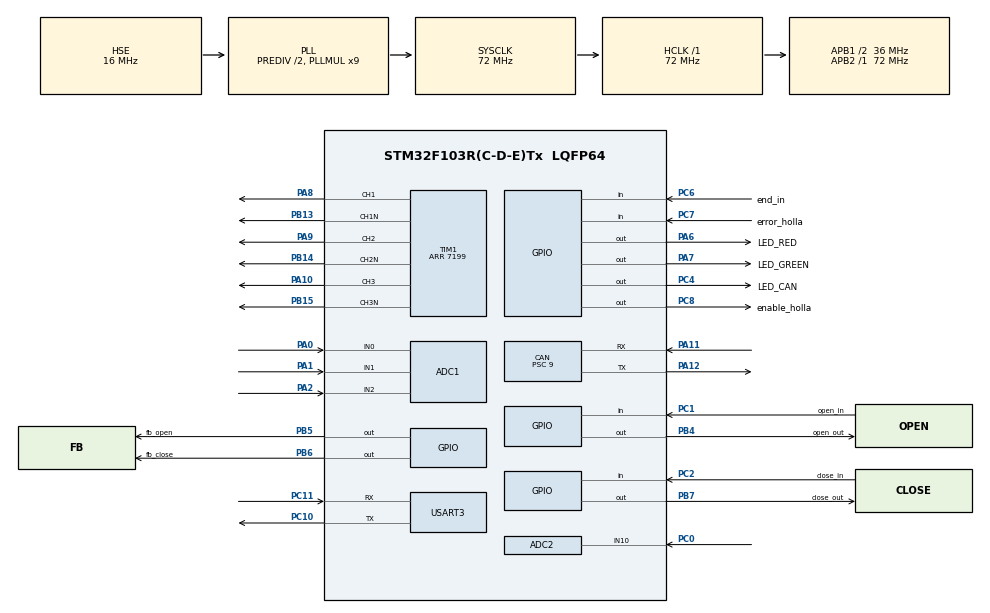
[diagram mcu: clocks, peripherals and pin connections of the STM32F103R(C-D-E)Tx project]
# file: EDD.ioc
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ADC1.Channel-0\#ChannelRegularConversion=ADC_CHANNEL_0
ADC1.Channel-1\#ChannelRegularConversion=ADC_CHANNEL_1
ADC1.Channel-2\#ChannelRegularConversion=ADC_CHANNEL_2
ADC1.NbrOfConversion=3
ADC1.NbrOfConversionFlag=1
ADC1.Rank-0\#ChannelRegularConversion=1
ADC1.Rank-1\#ChannelRegularConversion=2
ADC1.Rank-2\#ChannelRegularConversion=3
ADC1.SamplingTime-0\#ChannelRegularConversion=ADC_SAMPLETIME_13CYCLES_5
ADC1.SamplingTime-1\#ChannelRegularConversion=ADC_SAMPLETIME_13CYCLES_5
ADC1.SamplingTime-2\#ChannelRegularConversion=ADC_SAMPLETIME_13CYCLES_5
ADC1.master=1
ADC2.Channel-1\#ChannelInjectedConversion=ADC_CHANNEL_10
ADC2.EnableInjectedConversion=ENABLE
ADC2.EnableRegularConversion=DISABLE
ADC2.InjNumberOfConversion=1
ADC2.InjectedOffset-1\#ChannelInjectedConversion=0
ADC2.InjectedRank-1\#ChannelInjectedConversion=1
ADC2.SamplingTime-1\#ChannelInjectedConversion=ADC_SAMPLETIME_13CYCLES_5
CAN.ABOM=ENABLE
CAN.BS1=CAN_BS1_12TQ
CAN.BS2=CAN_BS2_3TQ
CAN.CalculateBaudRate=250000
CAN.CalculateTimeBit=4000
CAN.CalculateTimeQuantum=250.0
CAN.NART=ENABLE
CAN.Prescaler=9
CAN.TXFP=ENABLE
Dma.ADC1.0.Direction=DMA_PERIPH_TO_MEMORY
Dma.ADC1.0.Instance=DMA1_Channel1
Dma.ADC1.0.MemDataAlignment=DMA_MDATAALIGN_HALFWORD
Dma.ADC1.0.MemInc=DMA_MINC_ENABLE
Dma.ADC1.0.Mode=DMA_NORMAL
Dma.ADC1.0.PeriphDataAlignment=DMA_PDATAALIGN_HALFWORD
Dma.ADC1.0.PeriphInc=DMA_PINC_DISABLE
Dma.ADC1.0.Priority=DMA_PRIORITY_LOW
Dma.Request0=ADC1
Dma.Request1=USART3_TX
Dma.Request2=USART3_RX
Dma.USART3_RX.2.Direction=DMA_PERIPH_TO_MEMORY
Dma.USART3_RX.2.Instance=DMA1_Channel3
Dma.USART3_RX.2.MemDataAlignment=DMA_MDATAALIGN_BYTE
Dma.USART3_RX.2.MemInc=DMA_MINC_ENABLE
Dma.USART3_RX.2.Mode=DMA_NORMAL
Dma.USART3_RX.2.PeriphDataAlignment=DMA_PDATAALIGN_BYTE
Dma.USART3_RX.2.PeriphInc=DMA_PINC_DISABLE
Dma.USART3_RX.2.Priority=DMA_PRIORITY_LOW
Dma.USART3_TX.1.Direction=DMA_MEMORY_TO_PERIPH
Dma.USART3_TX.1.Instance=DMA1_Channel2
Dma.USART3_TX.1.MemDataAlignment=DMA_MDATAALIGN_BYTE
Dma.USART3_TX.1.MemInc=DMA_MINC_ENABLE
Dma.USART3_TX.1.Mode=DMA_NORMAL
Dma.USART3_TX.1.PeriphDataAlignment=DMA_PDATAALIGN_BYTE
Dma.USART3_TX.1.PeriphInc=DMA_PINC_DISABLE
Dma.USART3_TX.1.Priority=DMA_PRIORITY_LOW
Mcu.Family=STM32F1
Mcu.Name=STM32F103R(C-D-E)Tx
Mcu.Package=LQFP64
NVIC.ADC1_2_IRQn=true\:0\:0\:false\:false\:true\:true\:true
NVIC.DMA1_Channel1_IRQn=true\:0\:0\:false\:false\:true\:false\:true
NVIC.DMA1_Channel2_IRQn=true\:0\:0\:false\:false\:true\:false\:true
NVIC.DMA1_Channel3_IRQn=true\:0\:0\:false\:false\:true\:false\:true
NVIC.PriorityGroup=NVIC_PRIORITYGROUP_4
NVIC.TIM3_IRQn=true\:2\:0\:true\:false\:true\:true\:true
NVIC.USART3_IRQn=true\:0\:0\:false\:false\:true\:true\:true
NVIC.USB_LP_CAN1_RX0_IRQn=true\:0\:0\:false\:false\:true\:true\:true
PA0-WKUP.Signal=ADCx_IN0
PA1.Signal=ADCx_IN1
PA10.Signal=S_TIM1_CH3
PA11.Mode=CAN_Activate
PA11.Signal=CAN_RX
PA12.Mode=CAN_Activate
PA12.Signal=CAN_TX
PA13.Mode=Serial_Wire
PA13.Signal=SYS_JTMS-SWDIO
PA14.Mode=Serial_Wire
PA14.Signal=SYS_JTCK-SWCLK
PA2.Signal=ADCx_IN2
PA6.GPIO_Label=LED_RED
PA6.Signal=GPIO_Output
PA7.GPIO_Label=LED_GREEN
PA7.Signal=GPIO_Output
PA8.Signal=S_TIM1_CH1
PA9.Signal=S_TIM1_CH2
PB13.Mode=PWM Generation1 CH1 CH1N
PB13.Signal=TIM1_CH1N
PB14.Mode=PWM Generation2 CH2 CH2N
PB14.Signal=TIM1_CH2N
PB15.Mode=PWM Generation3 CH3 CH3N
PB15.Signal=TIM1_CH3N
PB4.GPIO_Label=open_out
PB4.Signal=GPIO_Output
PB5.GPIO_Label=fb_open
PB5.Signal=GPIO_Output
PB6.GPIO_Label=fb_close
PB6.Signal=GPIO_Output
PB7.GPIO_Label=close_out
PB7.Signal=GPIO_Output
PC0.Signal=ADCx_IN10
PC1.GPIO_Label=open_in
PC1.Signal=GPIO_Input
PC10.Mode=Asynchronous
PC10.Signal=USART3_TX
PC11.Mode=Asynchronous
PC11.Signal=USART3_RX
PC2.GPIO_Label=close_in
PC2.Signal=GPIO_Input
PC4.GPIO_Label=LED_CAN
PC4.Signal=GPIO_Output
PC6.GPIO_Label=end_in
PC6.Signal=GPIO_Input
PC7.GPIO_Label=error_holla
PC7.Signal=GPIO_Input
PC8.GPIO_Label=enable_holla
PC8.Signal=GPIO_Output
PD0-OSC_IN.Mode=HSE-External-Oscillator
PD0-OSC_IN.Signal=RCC_OSC_IN
PD1-OSC_OUT.Mode=HSE-External-Oscillator
PD1-OSC_OUT.Signal=RCC_OSC_OUT
ProjectManager.HeapSize=0x200
ProjectManager.StackSize=0x400
ProjectManager.TargetToolchain=STM32CubeIDE
RCC.ADCPresc=RCC_ADCPCLK2_DIV6
RCC.AHBFreq_Value=72000000
RCC.APB1CLKDivider=RCC_HCLK_DIV2
RCC.APB1Freq_Value=36000000
RCC.APB1TimFreq_Value=72000000
RCC.APB2Freq_Value=72000000
RCC.APB2TimFreq_Value=72000000
RCC.HCLKFreq_Value=72000000
RCC.HSEDivPLL=RCC_HSE_PREDIV_DIV2
RCC.HSE_VALUE=16000000
RCC.PLLMUL=RCC_PLL_MUL9
RCC.PLLSourceVirtual=RCC_PLLSOURCE_HSE
RCC.SYSCLKFreq_VALUE=72000000
RCC.SYSCLKSource=RCC_SYSCLKSOURCE_PLLCLK
RCC.USBFreq_Value=72000000
SH.ADCx_IN0.0=ADC1_IN0,IN0
SH.ADCx_IN1.0=ADC1_IN1,IN1
SH.ADCx_IN10.0=ADC2_IN10,IN10
SH.ADCx_IN2.0=ADC1_IN2,IN2
SH.S_TIM1_CH1.0=TIM1_CH1,PWM Generation1 CH1 CH1N
SH.S_TIM1_CH2.0=TIM1_CH2,PWM Generation2 CH2 CH2N
SH.S_TIM1_CH3.0=TIM1_CH3,PWM Generation3 CH3 CH3N
TIM1.Channel-PWM\ Generation1\ CH1\ CH1N=TIM_CHANNEL_1
TIM1.Channel-PWM\ Generation2\ CH2\ CH2N=TIM_CHANNEL_2
TIM1.Channel-PWM\ Generation3\ CH3\ CH3N=TIM_CHANNEL_3
TIM1.CounterMode=TIM_COUNTERMODE_CENTERALIGNED1
TIM1.DeadTime=115
TIM1.Period=7199
TIM3.AutoReloadPreload=TIM_AUTORELOAD_PRELOAD_ENABLE
TIM3.Channel-Output\ Compare1\ No\ Output=TIM_CHANNEL_1
TIM3.Period=49999
TIM3.Prescaler=39
USART3.VirtualMode=VM_ASYNC
VP_TIM3_VS_no_output1.Mode=Output Compare1 No Output
board=custom

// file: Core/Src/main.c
/* USER CODE BEGIN Header */
/**
  ******************************************************************************
  * @file           : main.c
  * @brief          : Main program body
  ******************************************************************************
  * @attention
  *
  * Copyright (c) 2024 STMicroelectronics.
  * All rights reserved.
  *
  * This software is licensed under terms that can be found in the LICENSE file
  * in the root directory of this software component.
  * If no LICENSE file comes with this software, it is provided AS-IS.
  *
  ******************************************************************************
  */
/* USER CODE END Header */
#include "main.h"

ADC_HandleTypeDef hadc1;
ADC_HandleTypeDef hadc2;
DMA_HandleTypeDef hdma_adc1;

CAN_HandleTypeDef hcan;

TIM_HandleTypeDef htim1;
TIM_HandleTypeDef htim3;

UART_HandleTypeDef huart3;
DMA_HandleTypeDef hdma_usart3_tx;
DMA_HandleTypeDef hdma_usart3_rx;

void SystemClock_Config(void);
static void MX_GPIO_Init(void);
static void MX_ADC1_Init(void);
static void MX_CAN_Init(void);
static void MX_TIM1_Init(void);
static void MX_DMA_Init(void);
static void MX_ADC2_Init(void);
static void MX_TIM3_Init(void);
static void MX_USART3_UART_Init(void);

int main(void)
{

  /* MCU Configuration--------------------------------------------------------*/

  /* Reset of all peripherals, Initializes the Flash interface and the Systick. */
  HAL_Init();

  /* Configure the system clock */
  SystemClock_Config();

  /* Initialize all configured peripherals */
  MX_GPIO_Init();
  MX_ADC1_Init();
  MX_CAN_Init();
  MX_TIM1_Init();
  MX_DMA_Init();
  MX_ADC2_Init();
  MX_TIM3_Init();
  MX_USART3_UART_Init();

  /* Infinite loop */
  while (1)
  {

  }
}

void SystemClock_Config(void)
{
  RCC_OscInitTypeDef RCC_OscInitStruct = {0};
  RCC_ClkInitTypeDef RCC_ClkInitStruct = {0};
  RCC_PeriphCLKInitTypeDef PeriphClkInit = {0};

  /** Initializes the RCC Oscillators according to the specified parameters
  * in the RCC_OscInitTypeDef structure.
  */
  RCC_OscInitStruct.OscillatorType = RCC_OSCILLATORTYPE_HSE;
  RCC_OscInitStruct.HSEState = RCC_HSE_ON;
  RCC_OscInitStruct.HSEPredivValue = RCC_HSE_PREDIV_DIV2;
  RCC_OscInitStruct.HSIState = RCC_HSI_ON;
  RCC_OscInitStruct.PLL.PLLState = RCC_PLL_ON;
  RCC_OscInitStruct.PLL.PLLSource = RCC_PLLSOURCE_HSE;
  RCC_OscInitStruct.PLL.PLLMUL = RCC_PLL_MUL9;
  if (HAL_RCC_OscConfig(&RCC_OscInitStruct) != HAL_OK)
  {
    Error_Handler();
  }
  /** Initializes the CPU, AHB and APB buses clocks
  */
  RCC_ClkInitStruct.ClockType = RCC_CLOCKTYPE_HCLK|RCC_CLOCKTYPE_SYSCLK
                              |RCC_CLOCKTYPE_PCLK1|RCC_CLOCKTYPE_PCLK2;
  RCC_ClkInitStruct.SYSCLKSource = RCC_SYSCLKSOURCE_PLLCLK;
  RCC_ClkInitStruct.AHBCLKDivider = RCC_SYSCLK_DIV1;
  RCC_ClkInitStruct.APB1CLKDivider = RCC_HCLK_DIV2;
  RCC_ClkInitStruct.APB2CLKDivider = RCC_HCLK_DIV1;

  if (HAL_RCC_ClockConfig(&RCC_ClkInitStruct, FLASH_LATENCY_2) != HAL_OK)
  {
    Error_Handler();
  }
  PeriphClkInit.PeriphClockSelection = RCC_PERIPHCLK_ADC;
  PeriphClkInit.AdcClockSelection = RCC_ADCPCLK2_DIV6;
  if (HAL_RCCEx_PeriphCLKConfig(&PeriphClkInit) != HAL_OK)
  {
    Error_Handler();
  }
}

static void MX_ADC1_Init(void)
{

  ADC_ChannelConfTypeDef sConfig = {0};

  /** Common config
  */
  hadc1.Instance = ADC1;
  hadc1.Init.ScanConvMode = ADC_SCAN_ENABLE;
  hadc1.Init.ContinuousConvMode = DISABLE;
  hadc1.Init.DiscontinuousConvMode = DISABLE;
  hadc1.Init.ExternalTrigConv = ADC_SOFTWARE_START;
  hadc1.Init.DataAlign = ADC_DATAALIGN_RIGHT;
  hadc1.Init.NbrOfConversion = 3;
  if (HAL_ADC_Init(&hadc1) != HAL_OK)
  {
    Error_Handler();
  }
  /** Configure Regular Channel
  */
  sConfig.Channel = ADC_CHANNEL_0;
  sConfig.Rank = ADC_REGULAR_RANK_1;
  sConfig.SamplingTime = ADC_SAMPLETIME_13CYCLES_5;
  if (HAL_ADC_ConfigChannel(&hadc1, &sConfig) != HAL_OK)
  {
    Error_Handler();
  }
  /** Configure Regular Channel
  */
  sConfig.Channel = ADC_CHANNEL_1;
  sConfig.Rank = ADC_REGULAR_RANK_2;
  if (HAL_ADC_ConfigChannel(&hadc1, &sConfig) != HAL_OK)
  {
    Error_Handler();
  }
  /** Configure Regular Channel
  */
  sConfig.Channel = ADC_CHANNEL_2;
  sConfig.Rank = ADC_REGULAR_RANK_3;
  if (HAL_ADC_ConfigChannel(&hadc1, &sConfig) != HAL_OK)
  {
    Error_Handler();
  }

}

static void MX_ADC2_Init(void)
{

  ADC_InjectionConfTypeDef sConfigInjected = {0};

  /** Common config
  */
  hadc2.Instance = ADC2;
  hadc2.Init.ScanConvMode = ADC_SCAN_DISABLE;
  hadc2.Init.ContinuousConvMode = DISABLE;
  hadc2.Init.DiscontinuousConvMode = DISABLE;
  hadc2.Init.ExternalTrigConv = ADC_SOFTWARE_START;
  hadc2.Init.DataAlign = ADC_DATAALIGN_RIGHT;
  hadc2.Init.NbrOfConversion = 1;
  if (HAL_ADC_Init(&hadc2) != HAL_OK)
  {
    Error_Handler();
  }
  /** Configure Injected Channel
  */
  sConfigInjected.InjectedChannel = ADC_CHANNEL_10;
  sConfigInjected.InjectedRank = ADC_INJECTED_RANK_1;
  sConfigInjected.InjectedNbrOfConversion = 1;
  sConfigInjected.InjectedSamplingTime = ADC_SAMPLETIME_13CYCLES_5;
  sConfigInjected.ExternalTrigInjecConv = ADC_INJECTED_SOFTWARE_START;
  sConfigInjected.AutoInjectedConv = DISABLE;
  sConfigInjected.InjectedDiscontinuousConvMode = DISABLE;
  sConfigInjected.InjectedOffset = 0;
  if (HAL_ADCEx_InjectedConfigChannel(&hadc2, &sConfigInjected) != HAL_OK)
  {
    Error_Handler();
  }

}

static void MX_CAN_Init(void)
{

  hcan.Instance = CAN1;
  hcan.Init.Prescaler = 9;
  hcan.Init.Mode = CAN_MODE_NORMAL;
  hcan.Init.SyncJumpWidth = CAN_SJW_1TQ;
  hcan.Init.TimeSeg1 = CAN_BS1_12TQ;
  hcan.Init.TimeSeg2 = CAN_BS2_3TQ;
  hcan.Init.TimeTriggeredMode = DISABLE;
  hcan.Init.AutoBusOff = ENABLE;
  hcan.Init.AutoWakeUp = DISABLE;
  hcan.Init.AutoRetransmission = ENABLE;
  hcan.Init.ReceiveFifoLocked = DISABLE;
  hcan.Init.TransmitFifoPriority = ENABLE;
  if (HAL_CAN_Init(&hcan) != HAL_OK)
  {
    Error_Handler();
  }

}

static void MX_TIM1_Init(void)
{

  TIM_MasterConfigTypeDef sMasterConfig = {0};
  TIM_OC_InitTypeDef sConfigOC = {0};
  TIM_BreakDeadTimeConfigTypeDef sBreakDeadTimeConfig = {0};

  htim1.Instance = TIM1;
  htim1.Init.Prescaler = 0;
  htim1.Init.CounterMode = TIM_COUNTERMODE_CENTERALIGNED1;
  htim1.Init.Period = 7199;
  htim1.Init.ClockDivision = TIM_CLOCKDIVISION_DIV1;
  htim1.Init.RepetitionCounter = 0;
  htim1.Init.AutoReloadPreload = TIM_AUTORELOAD_PRELOAD_DISABLE;
  if (HAL_TIM_PWM_Init(&htim1) != HAL_OK)
  {
    Error_Handler();
  }
  sMasterConfig.MasterOutputTrigger = TIM_TRGO_RESET;
  sMasterConfig.MasterSlaveMode = TIM_MASTERSLAVEMODE_DISABLE;
  if (HAL_TIMEx_MasterConfigSynchronization(&htim1, &sMasterConfig) != HAL_OK)
  {
    Error_Handler();
  }
  sConfigOC.OCMode = TIM_OCMODE_PWM1;
  sConfigOC.Pulse = 0;
  sConfigOC.OCPolarity = TIM_OCPOLARITY_HIGH;
  sConfigOC.OCNPolarity = TIM_OCNPOLARITY_HIGH;
  sConfigOC.OCFastMode = TIM_OCFAST_DISABLE;
  sConfigOC.OCIdleState = TIM_OCIDLESTATE_RESET;
  sConfigOC.OCNIdleState = TIM_OCNIDLESTATE_RESET;
  if (HAL_TIM_PWM_ConfigChannel(&htim1, &sConfigOC, TIM_CHANNEL_1) != HAL_OK)
  {
    Error_Handler();
  }
  if (HAL_TIM_PWM_ConfigChannel(&htim1, &sConfigOC, TIM_CHANNEL_2) != HAL_OK)
  {
    Error_Handler();
  }
  if (HAL_TIM_PWM_ConfigChannel(&htim1, &sConfigOC, TIM_CHANNEL_3) != HAL_OK)
  {
    Error_Handler();
  }
  sBreakDeadTimeConfig.OffStateRunMode = TIM_OSSR_DISABLE;
  sBreakDeadTimeConfig.OffStateIDLEMode = TIM_OSSI_DISABLE;
  sBreakDeadTimeConfig.LockLevel = TIM_LOCKLEVEL_OFF;
  sBreakDeadTimeConfig.DeadTime = 115;
  sBreakDeadTimeConfig.BreakState = TIM_BREAK_ENABLE;
  sBreakDeadTimeConfig.BreakPolarity = TIM_BREAKPOLARITY_HIGH;
  sBreakDeadTimeConfig.AutomaticOutput = TIM_AUTOMATICOUTPUT_DISABLE;
  if (HAL_TIMEx_ConfigBreakDeadTime(&htim1, &sBreakDeadTimeConfig) != HAL_OK)
  {
    Error_Handler();
  }
  HAL_TIM_MspPostInit(&htim1);

}

static void MX_TIM3_Init(void)
{

  TIM_MasterConfigTypeDef sMasterConfig = {0};
  TIM_OC_InitTypeDef sConfigOC = {0};

  htim3.Instance = TIM3;
  htim3.Init.Prescaler = 39;
  htim3.Init.CounterMode = TIM_COUNTERMODE_UP;
  htim3.Init.Period = 49999;
  htim3.Init.ClockDivision = TIM_CLOCKDIVISION_DIV1;
  htim3.Init.AutoReloadPreload = TIM_AUTORELOAD_PRELOAD_ENABLE;
  if (HAL_TIM_OC_Init(&htim3) != HAL_OK)
  {
    Error_Handler();
  }
  sMasterConfig.MasterOutputTrigger = TIM_TRGO_RESET;
  sMasterConfig.MasterSlaveMode = TIM_MASTERSLAVEMODE_DISABLE;
  if (HAL_TIMEx_MasterConfigSynchronization(&htim3, &sMasterConfig) != HAL_OK)
  {
    Error_Handler();
  }
  sConfigOC.OCMode = TIM_OCMODE_TIMING;
  sConfigOC.Pulse = 0;
  sConfigOC.OCPolarity = TIM_OCPOLARITY_HIGH;
  sConfigOC.OCFastMode = TIM_OCFAST_DISABLE;
  if (HAL_TIM_OC_ConfigChannel(&htim3, &sConfigOC, TIM_CHANNEL_1) != HAL_OK)
  {
    Error_Handler();
  }

}

static void MX_USART3_UART_Init(void)
{

  huart3.Instance = USART3;
  huart3.Init.BaudRate = 115200;
  huart3.Init.WordLength = UART_WORDLENGTH_8B;
  huart3.Init.StopBits = UART_STOPBITS_1;
  huart3.Init.Parity = UART_PARITY_NONE;
  huart3.Init.Mode = UART_MODE_TX_RX;
  huart3.Init.HwFlowCtl = UART_HWCONTROL_NONE;
  huart3.Init.OverSampling = UART_OVERSAMPLING_16;
  if (HAL_UART_Init(&huart3) != HAL_OK)
  {
    Error_Handler();
  }

}

static void MX_DMA_Init(void)
{

  /* DMA controller clock enable */
  __HAL_RCC_DMA1_CLK_ENABLE();

  /* DMA interrupt init */
  /* DMA1_Channel1_IRQn interrupt configuration */
  HAL_NVIC_SetPriority(DMA1_Channel1_IRQn, 0, 0);
  HAL_NVIC_EnableIRQ(DMA1_Channel1_IRQn);
  /* DMA1_Channel2_IRQn interrupt configuration */
  HAL_NVIC_SetPriority(DMA1_Channel2_IRQn, 0, 0);
  HAL_NVIC_EnableIRQ(DMA1_Channel2_IRQn);
  /* DMA1_Channel3_IRQn interrupt configuration */
  HAL_NVIC_SetPriority(DMA1_Channel3_IRQn, 0, 0);
  HAL_NVIC_EnableIRQ(DMA1_Channel3_IRQn);

}

static void MX_GPIO_Init(void)
{
  GPIO_InitTypeDef GPIO_InitStruct = {0};

  /* GPIO Ports Clock Enable */
  __HAL_RCC_GPIOD_CLK_ENABLE();
  __HAL_RCC_GPIOC_CLK_ENABLE();
  __HAL_RCC_GPIOA_CLK_ENABLE();
  __HAL_RCC_GPIOB_CLK_ENABLE();

  /*Configure GPIO pin Output Level */
  HAL_GPIO_WritePin(GPIOA, LED_RED_Pin|LED_GREEN_Pin, GPIO_PIN_RESET);

  /*Configure GPIO pin Output Level */
  HAL_GPIO_WritePin(GPIOC, LED_CAN_Pin|enable_holla_Pin, GPIO_PIN_RESET);

  /*Configure GPIO pin Output Level */
  HAL_GPIO_WritePin(GPIOB, open_out_Pin|fb_open_Pin|fb_close_Pin|close_out_Pin, GPIO_PIN_RESET);

  /*Configure GPIO pins : open_in_Pin close_in_Pin end_in_Pin error_holla_Pin */
  GPIO_InitStruct.Pin = open_in_Pin|close_in_Pin|end_in_Pin|error_holla_Pin;
  GPIO_InitStruct.Mode = GPIO_MODE_INPUT;
  GPIO_InitStruct.Pull = GPIO_NOPULL;
  HAL_GPIO_Init(GPIOC, &GPIO_InitStruct);

  /*Configure GPIO pins : LED_RED_Pin LED_GREEN_Pin */
  GPIO_InitStruct.Pin = LED_RED_Pin|LED_GREEN_Pin;
  GPIO_InitStruct.Mode = GPIO_MODE_OUTPUT_PP;
  GPIO_InitStruct.Pull = GPIO_NOPULL;
  GPIO_InitStruct.Speed = GPIO_SPEED_FREQ_LOW;
  HAL_GPIO_Init(GPIOA, &GPIO_InitStruct);

  /*Configure GPIO pins : LED_CAN_Pin enable_holla_Pin */
  GPIO_InitStruct.Pin = LED_CAN_Pin|enable_holla_Pin;
  GPIO_InitStruct.Mode = GPIO_MODE_OUTPUT_PP;
  GPIO_InitStruct.Pull = GPIO_NOPULL;
  GPIO_InitStruct.Speed = GPIO_SPEED_FREQ_LOW;
  HAL_GPIO_Init(GPIOC, &GPIO_InitStruct);

  /*Configure GPIO pin : holla_1_Pin */
  GPIO_InitStruct.Pin = holla_1_Pin;
  GPIO_InitStruct.Mode = GPIO_MODE_IT_RISING_FALLING;
  GPIO_InitStruct.Pull = GPIO_PULLUP;
  HAL_GPIO_Init(holla_1_GPIO_Port, &GPIO_InitStruct);

  /*Configure GPIO pins : holla_2_Pin holla_3_Pin */
  GPIO_InitStruct.Pin = holla_2_Pin|holla_3_Pin;
  GPIO_InitStruct.Mode = GPIO_MODE_IT_RISING_FALLING;
  GPIO_InitStruct.Pull = GPIO_PULLUP;
  HAL_GPIO_Init(GPIOB, &GPIO_InitStruct);

  /*Configure GPIO pins : open_out_Pin fb_open_Pin fb_close_Pin close_out_Pin */
  GPIO_InitStruct.Pin = open_out_Pin|fb_open_Pin|fb_close_Pin|close_out_Pin;
  GPIO_InitStruct.Mode = GPIO_MODE_OUTPUT_PP;
  GPIO_InitStruct.Pull = GPIO_NOPULL;
  GPIO_InitStruct.Speed = GPIO_SPEED_FREQ_LOW;
  HAL_GPIO_Init(GPIOB, &GPIO_InitStruct);

  /* EXTI interrupt init*/
  HAL_NVIC_SetPriority(EXTI0_IRQn, 0, 0);
  HAL_NVIC_EnableIRQ(EXTI0_IRQn);

  HAL_NVIC_SetPriority(EXTI1_IRQn, 0, 0);
  HAL_NVIC_EnableIRQ(EXTI1_IRQn);

  HAL_NVIC_SetPriority(EXTI9_5_IRQn, 0, 0);
  HAL_NVIC_EnableIRQ(EXTI9_5_IRQn);

}

void Error_Handler(void)
{
  __disable_irq();
  while (1)
  {
  }
}
